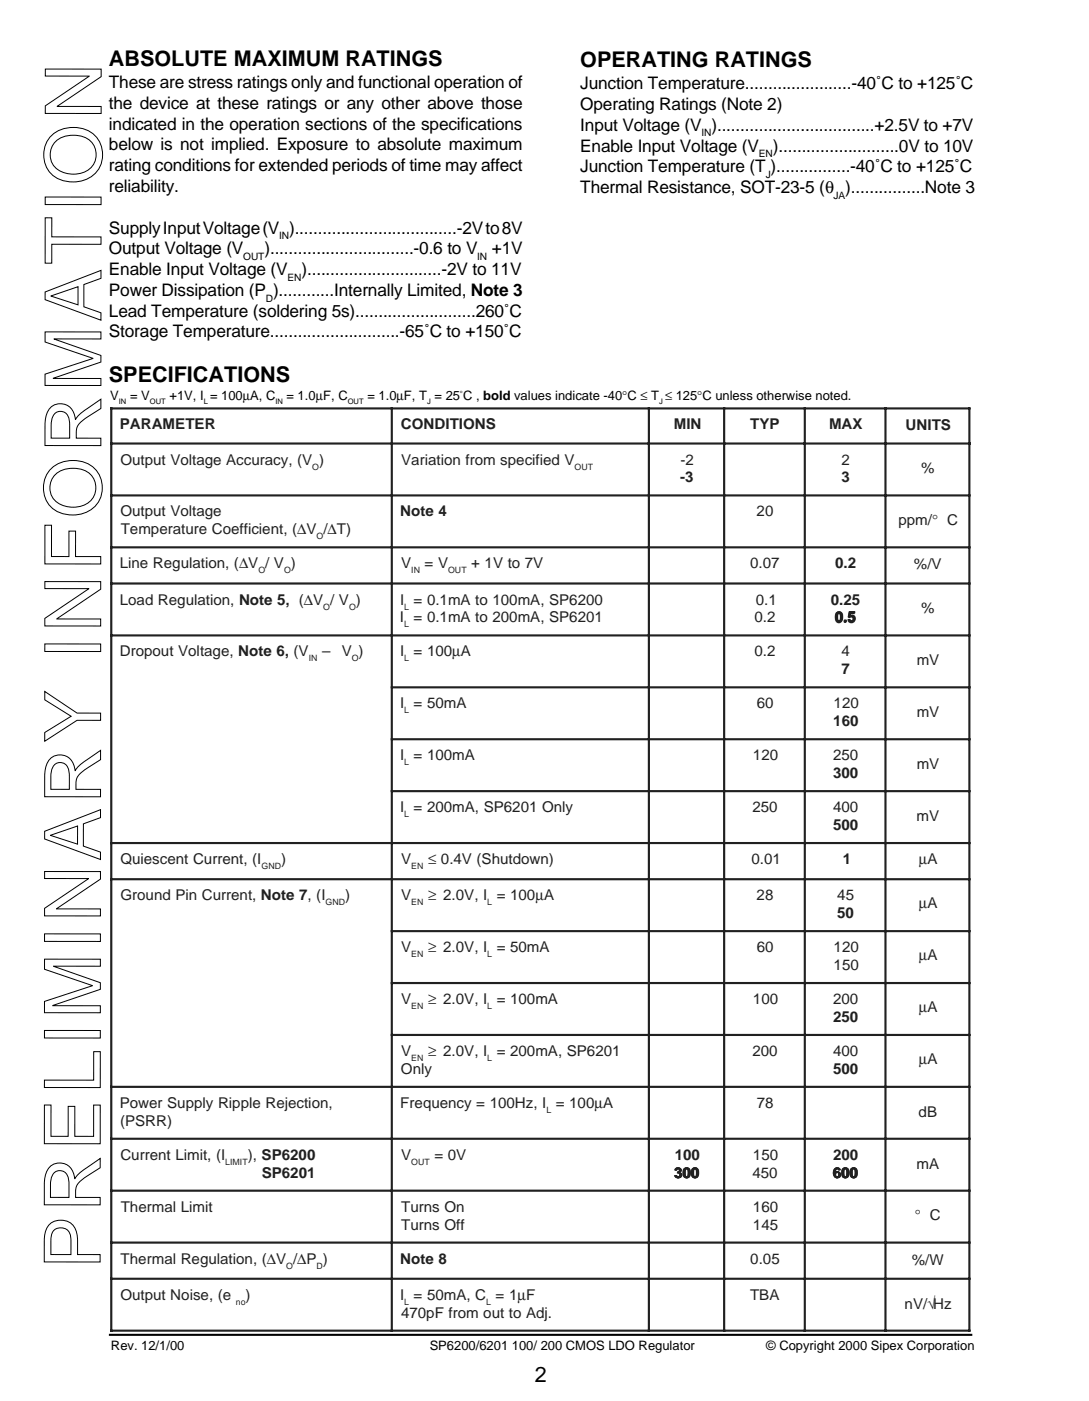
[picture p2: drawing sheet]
<svg xmlns="http://www.w3.org/2000/svg" width="178mm" height="229mm" viewBox="0 0 178 229" stroke-linecap="round" stroke-linejoin="round" font-family="sans-serif">
<defs><g id="words">
<text font-size="12.7" fill="#fff" x="16.3" y="207" transform="rotate(-90 16.3 207)">PRELIMINARY INFORMATION</text>
<g font-size="3.5">
<text x="17.8" y="10.8">ABSOLUTE MAXIMUM RATINGS</text>
<text x="94.7" y="10.9">OPERATING RATINGS</text>
<text x="17.8" y="62.4">SPECIFICATIONS</text>
<text x="87.3" y="225.6">2</text>
</g>
<g font-size="2.8">
<text x="17.8" y="14.4">These are stress ratings only and functional operation of</text>
<text x="17.8" y="17.8">the device at these ratings or any other above those</text>
<text x="94.7" y="14.6">Junction Temperature.......................-40˚C to +125˚C</text>
<text x="94.7" y="17.9">Operating Ratings (Note 2)</text>
<text x="17.8" y="21.2">indicated in the operation sections of the specifications</text>
<text x="94.7" y="21.3">Input Voltage (V )..................................+2.5V to +7V</text>
<text x="17.8" y="24.6">below is not implied. Exposure to absolute maximum</text>
<text x="17.8" y="27.9">rating conditions for extended periods of time may affect</text>
<text x="94.7" y="24.7">Enable Input Voltage (V</text>
<text x="94.7" y="28.1">Junction Temperature (T )................-40˚C to +125˚C</text>
<text x="126.2" y="24.7">)..........................0V to 10V</text>
<text x="17.8" y="31.3">reliability.</text>
<text x="94.7" y="31.5">Thermal Resistance, SOT-23-5 (θ )................Note 3</text>
<text x="17.8" y="38.1">Supply Input Voltage (V )...................................-2V to 8V</text>
<text x="17.8" y="41.5">Output Voltage (V</text>
<text x="43.2" y="41.5">)...............................-0.6 to V</text>
<text x="80.3" y="41.5">+1V</text>
<text x="17.8" y="44.9">Enable Input Voltage (V</text>
<text x="49.2" y="44.9">).............................-2V to 11V</text>
<text x="17.8" y="48.3">Power Dissipation (P )............Internally Limited, Note 3</text>
<text x="17.8" y="51.6">Lead Temperature (soldering 5s)..........................260˚C</text>
<text x="17.8" y="55">Storage Temperature............................-65˚C to +150˚C</text>
</g>
<g font-size="2.4" fill="#231f20">
<text x="19.6" y="70.1">PARAMETER</text>
<text x="65.5" y="70.1">CONDITIONS</text>
<text x="110" y="70.1">MIN</text>
<text x="122.5" y="70.1">TYP</text>
<text x="135.4" y="70.1">MAX</text>
<text x="147.9" y="70.2">UNITS</text>
<text x="19.7" y="75.8">Output Voltage Accuracy, (V )</text>
<text x="65.5" y="75.8">Variation from specified V</text>
<text x="111.1" y="75.8">-2</text>
<text x="137.4" y="75.8">2</text>
<text x="150.4" y="77.3">%</text>
<text x="111.1" y="78.7">-3</text>
<text x="137.4" y="78.7">3</text>
<text x="19.7" y="84.3">Output Voltage</text>
<text x="19.7" y="87.2">Temperature Coefficient, (∆V /∆T)</text>
<text x="65.4" y="84.3">Note 4</text>
<text x="123.5" y="84.3">20</text>
<text x="146.7" y="85.7">ppm/° C</text>
<text x="19.6" y="92.7">Line Regulation, (∆V / V )</text>
<text x="65.5" y="92.7">V</text>
<text x="69.3" y="92.7">= V</text>
<text x="76.9" y="92.7">+ 1V to 7V</text>
<text x="122.5" y="92.7">0.07</text>
<text x="136.3" y="92.7">0.2</text>
<text x="149.2" y="92.9">%/V</text>
<text x="19.6" y="98.6">Load Regulation, Note 5, (∆V / V )</text>
<text x="65.3" y="101.6">I = 0.1mA to 200mA, SP6201</text>
<text x="65.3" y="98.6">I = 0.1mA to 100mA, SP6200</text>
<text x="123.2" y="101.6">0.2</text>
<text x="123.4" y="98.6">0.1</text>
<text x="135.7" y="98.6">0.25</text>
<text x="136.3" y="101.6">0.5</text>
<text x="150.4" y="100.1">%</text>
<text x="19.6" y="107.1">Dropout Voltage, Note 6, (V</text>
<text x="52.6" y="107.1">–</text>
<text x="55.8" y="107.1">V )</text>
<text x="65.3" y="107.1">I = 100µA</text>
<text x="123.2" y="107.1">0.2</text>
<text x="137.4" y="107.1">4</text>
<text x="137.4" y="110">7</text>
<text x="149.7" y="108.6">mV</text>
<text x="65.3" y="115.6">I = 50mA</text>
<text x="123.5" y="115.6">60</text>
<text x="136.1" y="118.5">160</text>
<text x="136.1" y="115.6">120</text>
<text x="149.7" y="117">mV</text>
<text x="65.3" y="124.1">I = 100mA</text>
<text x="122.9" y="124.1">120</text>
<text x="136" y="124.1">250</text>
<text x="149.7" y="125.5">mV</text>
<text x="136" y="127">300</text>
<text x="65.3" y="132.5">I = 200mA, SP6201 Only</text>
<text x="122.8" y="132.5">250</text>
<text x="136" y="135.4">500</text>
<text x="136" y="132.5">400</text>
<text x="149.7" y="134">mV</text>
<text x="19.7" y="141">Quiescent Current, (I</text>
<text x="45.9" y="141">)</text>
<text x="65.5" y="141">V</text>
<text x="69.9" y="141">≤ 0.4V (Shutdown)</text>
<text x="122.7" y="141">0.01</text>
<text x="137.6" y="141">1</text>
<text x="150" y="141">µA</text>
<text x="19.7" y="146.9">Ground Pin Current, Note 7, (I</text>
<text x="56.3" y="146.9">)</text>
<text x="65.5" y="146.9">V</text>
<text x="69.9" y="146.9">≥ 2.0V, I = 100µA</text>
<text x="123.5" y="146.9">28</text>
<text x="136.7" y="149.8">50</text>
<text x="136.7" y="146.9">45</text>
<text x="150" y="148.2">µA</text>
<text x="65.5" y="155.4">V</text>
<text x="69.9" y="155.4">≥ 2.0V, I = 50mA</text>
<text x="123.5" y="155.4">60</text>
<text x="136.1" y="155.4">120</text>
<text x="136.1" y="158.3">150</text>
<text x="150" y="156.7">µA</text>
<text x="65.5" y="163.8">V</text>
<text x="69.9" y="163.8">≥ 2.0V, I = 100mA</text>
<text x="122.9" y="163.8">100</text>
<text x="136" y="166.8">250</text>
<text x="136" y="163.8">200</text>
<text x="150" y="165.1">µA</text>
<text x="65.5" y="172.3">V</text>
<text x="69.9" y="172.3">≥ 2.0V, I = 200mA, SP6201</text>
<text x="122.8" y="172.3">200</text>
<text x="136" y="172.3">400</text>
<text x="150" y="173.6">µA</text>
<text x="65.5" y="175.2">Only</text>
<text x="136" y="175.2">500</text>
<text x="19.6" y="180.8">Power Supply Ripple Rejection,</text>
<text x="19.6" y="183.7">(PSRR)</text>
<text x="65.4" y="180.8">Frequency = 100Hz, I = 100µA</text>
<text x="123.5" y="180.8">78</text>
<text x="150" y="182.2">dB</text>
<text x="19.7" y="189.2">Current Limit, (I</text>
<text x="40.5" y="189.2">), SP6200</text>
<text x="65.5" y="189.2">V</text>
<text x="70.9" y="189.2">= 0V</text>
<text x="110.2" y="189.2">100</text>
<text x="122.9" y="189.2">150</text>
<text x="136" y="189.2">200</text>
<text x="149.7" y="190.7">mA</text>
<text x="19.7" y="197.7">Thermal Limit</text>
<text x="42.7" y="192.2">SP6201</text>
<text x="65.5" y="197.7">Turns On</text>
<text x="110.1" y="192.2">300</text>
<text x="122.8" y="192.2">450</text>
<text x="122.9" y="197.7">160</text>
<text x="136" y="192.2">600</text>
<text x="65.5" y="200.6">Turns Off</text>
<text x="122.9" y="200.6">145</text>
<text x="149.3" y="199">° C</text>
<text x="19.7" y="206.2">Thermal Regulation, (∆V /∆P )</text>
<text x="65.4" y="206.2">Note 8</text>
<text x="122.5" y="206.2">0.05</text>
<text x="148.9" y="206.4">%/W</text>
<text x="19.7" y="212.1">Output Noise, (e</text>
<text x="40.1" y="212.1">)</text>
<text x="65.3" y="212.1">I = 50mA, C = 1µF</text>
<text x="65.5" y="215">470pF from out to Adj.</text>
<text x="122.5" y="212.1">TBA</text>
<text x="147.7" y="213.5">nV/√Hz</text>
</g>
<g font-size="2.1">
<text x="18" y="65.3">V</text>
<text x="21.2" y="65.3">= V</text>
<text x="27.7" y="65.3">+1V, I = 100µA, C</text>
<text x="46.8" y="65.3">= 1.0µF, C</text>
<text x="60" y="65.3">= 1.0µF, T = 25 C , bold values indicate -40°C ≤ T ≤ 125°C unless otherwise noted.</text>
<text x="18.1" y="220.2">Rev. 12/1/00</text>
<text x="70.2" y="220.2">SP6200/6201 100/ 200 CMOS LDO Regulator</text>
<text x="125.1" y="220.2">© Copyright 2000 Sipex Corporation</text>
</g>
<g font-size="1.7">
<text x="114.5" y="22.3">IN</text>
<text x="123.9" y="25.7">EN</text>
<text x="125" y="29">J</text>
<text x="136.1" y="32.4">JA</text>
<text x="45.6" y="39.1">IN</text>
<text x="39.7" y="42.5">OUT</text>
<text x="46.9" y="45.8">EN</text>
<text x="77.9" y="42.5">IN</text>
<text x="43.4" y="49.2">D</text>
</g>
<g font-size="1.4" fill="#231f20">
<text x="51" y="76.6">O</text>
<text x="93.8" y="76.6">OUT</text>
<text x="51.7" y="88">O</text>
<text x="42.2" y="93.6">O</text>
<text x="46.4" y="93.6">O</text>
<text x="67.2" y="93.6">IN</text>
<text x="73.2" y="93.6">OUT</text>
<text x="52.8" y="99.5">O</text>
<text x="57" y="99.5">O</text>
<text x="66" y="99.5">L</text>
<text x="50.4" y="107.9">IN</text>
<text x="57.4" y="107.9">O</text>
<text x="66" y="102.4">L</text>
<text x="66" y="107.9">L</text>
<text x="66" y="116.4">L</text>
<text x="66" y="124.9">L</text>
<text x="66" y="133.3">L</text>
<text x="42.7" y="141.8">GND</text>
<text x="67.2" y="141.8">EN</text>
<text x="53.2" y="147.7">GND</text>
<text x="67.2" y="147.7">EN</text>
<text x="79.6" y="147.7">L</text>
<text x="67.2" y="156.2">EN</text>
<text x="79.6" y="156.2">L</text>
<text x="67.2" y="164.6">EN</text>
<text x="79.6" y="164.6">L</text>
<text x="67.2" y="173.1">EN</text>
<text x="79.6" y="173.1">L</text>
<text x="89.2" y="181.6">L</text>
<text x="36.8" y="190.1">LIMIT</text>
<text x="67.2" y="190.1">OUT</text>
<text x="46.7" y="207">O</text>
<text x="51.7" y="207">D</text>
<text x="38.5" y="212.9">no</text>
<text x="66" y="212.9">L</text>
<text x="79.4" y="212.9">L</text>
</g>
<g font-size="1.2">
<text x="19.4" y="66">IN</text>
<text x="24.5" y="66">OUT</text>
<text x="33.3" y="66">L</text>
<text x="45" y="66">IN</text>
<text x="56.8" y="66">OUT</text>
<text x="69.7" y="66">J</text>
<text x="75.1" y="64.6">°</text>
<text x="107.6" y="66">J</text>
</g>
</g></defs>
<path d="M17.8 217.8h140.9" fill="none" stroke="#000" stroke-width=".34"/>
<g fill="none" stroke="#231f20" stroke-width=".35">
<path d="M18 66.6h140.4M18 72.4h140.4M18.2 66.5v150.8M64 66.5v150.8M105.9 66.5v150.8M118.2 66.5v150.8M131.4 66.5v150.8M144.6 66.5v150.8M158.3 66.5v150.8M18 80.8h140.4M18 89.3h140.4M18 95.2h140.4"/>
<path d="M18 103.7h140.4M63.8 112.2h94.6M18 137.6h140.4M63.8 120.6h94.6M63.8 129.1h94.6M18 143.5h140.4M63.8 151.9h94.6M18 177.3h140.4M63.8 160.4h94.6M63.8 168.9h94.6M18 185.8h140.4M18 194.3h140.4"/>
<path d="M18 202.8h140.4M18 208.7h140.4M18 217.1h140.4"/>
</g>
<use href="#words"/>
</svg>
